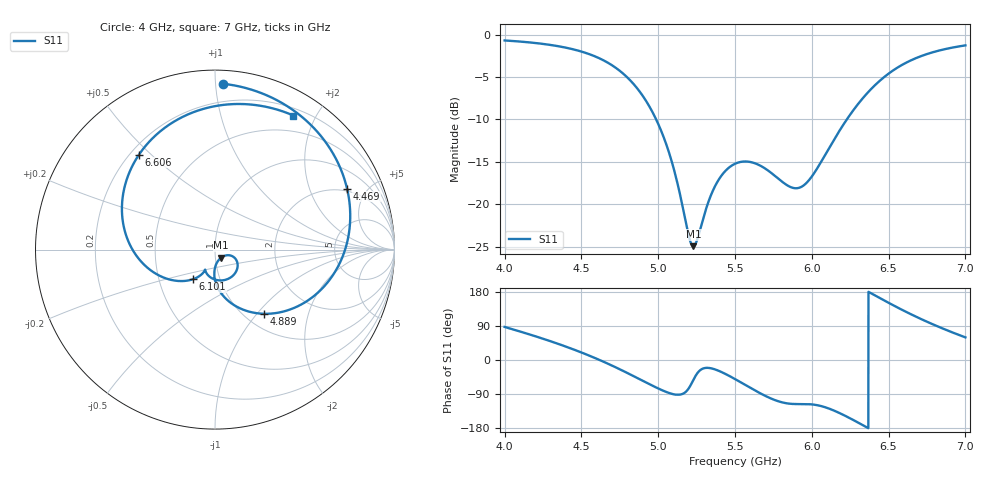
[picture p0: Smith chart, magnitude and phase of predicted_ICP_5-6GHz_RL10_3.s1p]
! ICP-predicted S11, target 5.000-6.000 GHz at -10 dB. Complex ensemble mean (passive and causal);
! its |S11| can differ slightly from the dB-domain mean reported in designs.csv.
!  Air_gap = 2.46mm
!  W_Patch = 14.58mm
!  L_Patch = 17.51mm
!  Sx = 0.5mm
!  Sy = 3.12mm
!  W_Patch1 = 11.73mm
!  WS = 0.53mm
!  Curve_Amp1 = 0.59mm
!  Extra = 4.31mm
# GHz S MA R 50
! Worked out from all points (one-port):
!   3001 points, 4 GHz to 7 GHz, reference 50 ohm
!   lowest |S11| = -25.0 dB at 5.229 GHz (marker M1), VSWR 1.12, Z = 53.3 - j4.8 ohm
!   |S11| at or under -10 dB: 4.987 GHz to 6.228 GHz (1.241 GHz wide, 22.1 % of centre)
!   S11 on the Smith chart (normalised r, x): 4 GHz: 0.08, +1.05; 4.469 GHz: 1.86, +3.67; 4.889 GHz: 1.21, -1.09; 6.101 GHz: 0.74, -0.26; 6.606 GHz: 0.23, +0.46; 7 GHz: 0.29, +1.71
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4  0.9252 87.3
4.187  0.8964 64.4
4.375  0.8473 38.8
4.469  0.8104 24.8
4.61  0.7309 1.5
4.75  0.6122 -24.5
4.821  0.5343 -38.7
4.889  0.4494 -52.7
5.022  0.2672 -79.2
5.125  0.1332 -91.5
5.199  0.06486 -74.6
5.229  0.05651 -52.5
5.371  0.1282 -25.0
5.5  0.1731 -50.3
5.641  0.1728 -82.8
5.875  0.125 -116.0
5.97  0.1348 -116.3
6.101  0.2055 -126.6
6.25  0.338 -154.0
6.342  0.4324 -174.1
6.444  0.5363 163.2
6.524  0.611 145.7
6.606  0.6778 128.6
6.625  0.6917 124.8
6.718  0.7516 106.8
6.807  0.797 90.8
6.898  0.8336 75.6
7  0.8653 59.7
